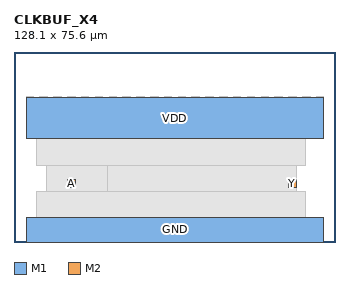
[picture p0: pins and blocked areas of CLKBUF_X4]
MACRO CLKBUF_X4
  CLASS CORE ;
  ORIGIN 0 0 ;
  SIZE 128.100 BY 75.600 ;
  SYMMETRY X Y ;
  SITE TR1um_access_site ;
  PIN VDD
    DIRECTION INOUT ;
    USE POWER ;
    PORT
      LAYER M1 ;
        RECT 5.000 41.000 123.100 57.600 ;
    END
  END VDD
  PIN GND
    DIRECTION INOUT ;
    USE GROUND ;
    PORT
      LAYER M1 ;
        RECT 5.000 0.000 123.100 9.800 ;
    END
  END GND
  PIN A
    DIRECTION INPUT ;
    USE SIGNAL ;
    PORT
      LAYER M2 ;
        RECT 21.100 21.600 24.500 25.000 ;
    END
  END A
  PIN Y
    DIRECTION OUTPUT ;
    USE SIGNAL ;
    PORT
      LAYER M2 ;
        RECT 109.100 21.600 112.500 25.000 ;
    END
  END Y
  OBS
    LAYER M1 ;
      RECT 15.100 16.400 29.700 34.400 ;
    LAYER M1 ;
      RECT 13.100 6.400 105.700 51.200 ;
    LAYER M1 ;
      RECT 37.100 6.400 112.500 51.200 ;
    LAYER V1 ;
      RECT 4.800 0.000 7.800 2.800 ;
    LAYER V1 ;
      RECT 10.300 0.000 13.300 2.800 ;
    LAYER V1 ;
      RECT 15.800 0.000 18.800 2.800 ;
    LAYER V1 ;
      RECT 21.300 0.000 24.300 2.800 ;
    LAYER V1 ;
      RECT 26.800 0.000 29.800 2.800 ;
    LAYER V1 ;
      RECT 32.300 0.000 35.300 2.800 ;
    LAYER V1 ;
      RECT 37.800 0.000 40.800 2.800 ;
    LAYER V1 ;
      RECT 43.300 0.000 46.300 2.800 ;
    LAYER V1 ;
      RECT 48.800 0.000 51.800 2.800 ;
    LAYER V1 ;
      RECT 54.300 0.000 57.300 2.800 ;
    LAYER V1 ;
      RECT 59.800 0.000 62.800 2.800 ;
    LAYER V1 ;
      RECT 65.300 0.000 68.300 2.800 ;
    LAYER V1 ;
      RECT 70.800 0.000 73.800 2.800 ;
    LAYER V1 ;
      RECT 76.300 0.000 79.300 2.800 ;
    LAYER V1 ;
      RECT 81.800 0.000 84.800 2.800 ;
    LAYER V1 ;
      RECT 87.300 0.000 90.300 2.800 ;
    LAYER V1 ;
      RECT 92.800 0.000 95.800 2.800 ;
    LAYER V1 ;
      RECT 98.300 0.000 101.300 2.800 ;
    LAYER V1 ;
      RECT 103.800 0.000 106.800 2.800 ;
    LAYER V1 ;
      RECT 109.300 0.000 112.300 2.800 ;
    LAYER V1 ;
      RECT 114.800 0.000 117.800 2.800 ;
    LAYER V1 ;
      RECT 120.300 0.000 123.300 2.800 ;
    LAYER V1 ;
      RECT 8.900 4.000 115.900 20.200 ;
    LAYER V1 ;
      RECT 22.100 22.600 23.500 24.000 ;
    LAYER V1 ;
      RECT 110.100 22.600 111.500 24.000 ;
    LAYER V1 ;
      RECT 8.900 30.600 115.900 53.600 ;
    LAYER V1 ;
      RECT 4.800 54.800 7.800 57.800 ;
    LAYER V1 ;
      RECT 10.300 54.800 13.300 57.800 ;
    LAYER V1 ;
      RECT 15.800 54.800 18.800 57.800 ;
    LAYER V1 ;
      RECT 21.300 54.800 24.300 57.800 ;
    LAYER V1 ;
      RECT 26.800 54.800 29.800 57.800 ;
    LAYER V1 ;
      RECT 32.300 54.800 35.300 57.800 ;
    LAYER V1 ;
      RECT 37.800 54.800 40.800 57.800 ;
    LAYER V1 ;
      RECT 43.300 54.800 46.300 57.800 ;
    LAYER V1 ;
      RECT 48.800 54.800 51.800 57.800 ;
    LAYER V1 ;
      RECT 54.300 54.800 57.300 57.800 ;
    LAYER V1 ;
      RECT 59.800 54.800 62.800 57.800 ;
    LAYER V1 ;
      RECT 65.300 54.800 68.300 57.800 ;
    LAYER V1 ;
      RECT 70.800 54.800 73.800 57.800 ;
    LAYER V1 ;
      RECT 76.300 54.800 79.300 57.800 ;
    LAYER V1 ;
      RECT 81.800 54.800 84.800 57.800 ;
    LAYER V1 ;
      RECT 87.300 54.800 90.300 57.800 ;
    LAYER V1 ;
      RECT 92.800 54.800 95.800 57.800 ;
    LAYER V1 ;
      RECT 98.300 54.800 101.300 57.800 ;
    LAYER V1 ;
      RECT 103.800 54.800 106.800 57.800 ;
    LAYER V1 ;
      RECT 109.300 54.800 112.300 57.800 ;
    LAYER V1 ;
      RECT 114.800 54.800 117.800 57.800 ;
    LAYER V1 ;
      RECT 120.300 54.800 123.300 57.800 ;
  END
END CLKBUF_X4
